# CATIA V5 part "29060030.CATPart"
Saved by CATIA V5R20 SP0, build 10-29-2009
Part number: 29060030
Definition: NONE
Nomenclature: 29060030
Source: Unknown
Description: 29060030
Bounding box of the stored display mesh (mm): x -15 to 44.548, y -44 to 78.548, z -34 to 34
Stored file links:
  C:\Users\Utente\Desktop\IO LAVORO\3D X SITO CF\X SITO\PLASTICA\RF1\29060030.CATPart

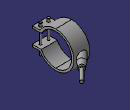
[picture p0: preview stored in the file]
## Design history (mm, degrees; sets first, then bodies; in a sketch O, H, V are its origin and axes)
Body1 "29060030" (main body)
  Solid1: solid without history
